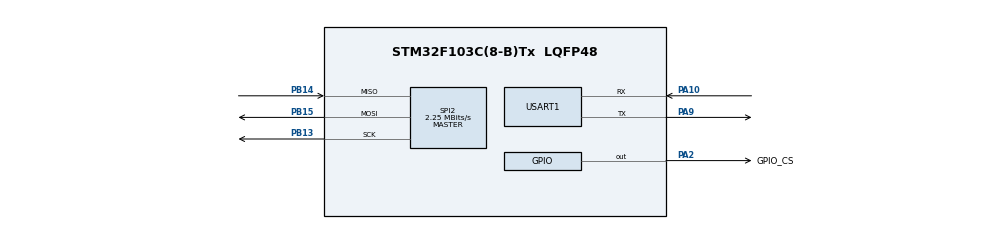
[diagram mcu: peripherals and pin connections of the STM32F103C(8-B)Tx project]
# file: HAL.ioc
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Mcu.Family=STM32F1
Mcu.Name=STM32F103C(8-B)Tx
Mcu.Package=LQFP48
NVIC.PriorityGroup=NVIC_PRIORITYGROUP_4
PA2.GPIO_Label=GPIO_CS
PA2.Signal=GPIO_Output
PA9.Mode=Asynchronous
PA9.Signal=USART1_TX
PA10.Mode=Asynchronous
PA10.Signal=USART1_RX
PA13.Mode=Serial_Wire
PA13.Signal=SYS_JTMS-SWDIO
PA14.Mode=Serial_Wire
PA14.Signal=SYS_JTCK-SWCLK
PB13.Mode=NSS_Signal_Hard_Or_Soft
PB13.Signal=SPI2_SCK
PB14.Mode=NSS_Signal_Hard_Or_Soft
PB14.Signal=SPI2_MISO
PB15.Mode=NSS_Signal_Hard_Or_Soft
PB15.Signal=SPI2_MOSI
ProjectManager.HeapSize=0x200
ProjectManager.StackSize=0x400
ProjectManager.TargetToolchain=MDK-ARM V5.32
RCC.AHBFreq_Value=72000000
RCC.APB1Freq_Value=36000000
RCC.APB1TimFreq_Value=72000000
RCC.APB2Freq_Value=72000000
RCC.APB2TimFreq_Value=72000000
RCC.HCLKFreq_Value=72000000
RCC.HSE_VALUE=8000000
RCC.HSI_VALUE=8000000
RCC.PLLMUL=RCC_PLL_MUL9
RCC.SYSCLKFreq_VALUE=72000000
RCC.SYSCLKSource=RCC_SYSCLKSOURCE_PLLCLK
RCC.USBFreq_Value=36000000
SPI2.CalculateBaudRate=2.25 MBits/s
SPI2.Direction=SPI_DIRECTION_2LINES
SPI2.Mode=SPI_MODE_MASTER
SPI2.BaudRatePrescaler=SPI_BAUDRATEPRESCALER_16
SPI2.VirtualType=VM_MASTER
board=custom

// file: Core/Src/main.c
/* USER CODE BEGIN Header */
/**
  ******************************************************************************
  * @file           : main.c
  * @brief          : Main program body
  ******************************************************************************
  * @attention
  *
  * Copyright (c) 2026 STMicroelectronics.
  * All rights reserved.
  *
  * This software is licensed under terms that can be found in the LICENSE file
  * in the root directory of this software component.
  * If no LICENSE file comes with this software, it is provided AS-IS.
  *
  ******************************************************************************
  */
/* USER CODE END Header */
#include "main.h"
#include "gpio.h"
#include "spi.h"
#include "usart.h"

/* USER CODE BEGIN Includes */
#include "g356_driver.h"
/* USER CODE END Includes */

void SystemClock_Config(void);

/* USER CODE BEGIN 0 */

// ==========================================================================
// G356 SPI Receiver Demo
//
// This file only demonstrates how to call the reusable G356 driver
// (g356_driver.h/.c). If you're integrating G356 into your own product,
// you only need to copy g356_driver.h/.c — the retry loop, success/fail
// statistics, and pretty-printing below are demo-only and can be deleted.
//
// Wiring and protocol details: see g356_driver.h and ../README.md.
// ==========================================================================

// ==========================================
// 调试串口输出辅助函数 (避免依赖大体积的 C 库 printf 及其浮点支持)
// ==========================================
static void G356_UART_PrintString(const char *str)
{
    while (*str) {
        HAL_UART_Transmit(&huart1, (uint8_t *)str, 1, 10);
        str++;
    }
}

static void G356_UART_PrintUint(uint32_t val)
{
    char buf[12];
    int i = 11;
    buf[i] = '\0';
    if (val == 0) {
        G356_UART_PrintString("0");
        return;
    }
    while (val > 0) {
        i--;
        buf[i] = (val % 10) + '0';
        val /= 10;
    }
    G356_UART_PrintString(&buf[i]);
}

static void G356_UART_PrintHex8(uint8_t val)
{
    const char hex_chars[] = "0123456789ABCDEF";
    char buf[3];
    buf[0] = hex_chars[(val >> 4) & 0x0F];
    buf[1] = hex_chars[val & 0x0F];
    buf[2] = '\0';
    G356_UART_PrintString(buf);
}

static void G356_UART_PrintFloat(float val, int decimals)
{
    // 处理负数
    if (val < 0.0f) {
        G356_UART_PrintString("-");
        val = -val;
    }

    // 四舍五入处理
    float rounding = 0.5f;
    for (int d = 0; d < decimals; d++) {
        rounding /= 10.0f;
    }
    val += rounding;

    // 整数部分
    uint32_t int_part = (uint32_t)val;
    G356_UART_PrintUint(int_part);

    // 小数部分
    if (decimals > 0) {
        G356_UART_PrintString(".");
        float frac = val - (float)int_part;
        for (int d = 0; d < decimals; d++) {
            frac *= 10.0f;
            uint32_t digit = (uint32_t)frac;
            G356_UART_PrintUint(digit);
            frac -= (float)digit;
        }
    }
}

/* USER CODE END 0 */

int main(void)
{

  /* MCU Configuration--------------------------------------------------------*/

  /* Reset of all peripherals, Initializes the Flash interface and the Systick. */
  HAL_Init();

  /* Configure the system clock */
  SystemClock_Config();

  /* Initialize all configured peripherals */
  MX_GPIO_Init();
  MX_SPI2_Init();
  MX_USART1_UART_Init();
  /* USER CODE BEGIN 2 */

  HAL_Delay(1000); // 等待 G356 模块内部系统彻底启动并稳定

  G356_UART_PrintString("\r\n");
  G356_UART_PrintString("=========================================\r\n");
  G356_UART_PrintString("   G356 AHRS Module SPI Receiver Demo    \r\n");
  G356_UART_PrintString("   MCU: STM32F103C8T6 | Baudrate: 115200 \r\n");
  G356_UART_PrintString("   Communication: SPI2 (Mode 0, ~2MHz)   \r\n");
  G356_UART_PrintString("=========================================\r\n");
  G356_UART_PrintString("Starting data reading...\r\n");

  uint8_t rx_raw_buf[G356_MAX_FRAME_SIZE]; // 原始接收缓冲区
  uint16_t rx_frame_size = 0;
  G356_Data_t g356_data;               // 解析后的姿态数据结构体
  uint32_t success_count = 0;          // 成功包计数
  uint32_t fail_count = 0;             // 失败包计数

  /* USER CODE END 2 */

  /* Infinite loop */
  while (1)
  {

    /* USER CODE BEGIN 3 */
    HAL_Delay(10); // 实现约 100Hz 的轮询读取速率

    // 根据帧头长度读取当前固件配置的 48/56/72 字节遥测帧。
    bool read_ok = false;
    for (int retry = 0; retry < 3; retry++) {
        if (G356_ReadFrame(rx_raw_buf, &rx_frame_size)) {
            read_ok = true;
            break;
        }
        HAL_Delay(1); // 每次失败后等待从机复位/预装载完毕再试
    }

    if (read_ok) {
        success_count++;

        G356_ParseData(rx_raw_buf, &g356_data);

        // 每成功读取 20 次 (约 200ms) 打印一次数据，防止串口拥堵
        if (success_count % 20 == 0) {
            G356_UART_PrintString("ANG[R:");
            G356_UART_PrintFloat(g356_data.roll, 2);
            G356_UART_PrintString(", P:");
            G356_UART_PrintFloat(g356_data.pitch, 2);
            G356_UART_PrintString(", Y:");
            G356_UART_PrintFloat(g356_data.yaw, 2);

            G356_UART_PrintString("] deg | ACC[");
            G356_UART_PrintFloat(g356_data.accel_x, 3);
            G356_UART_PrintString(", ");
            G356_UART_PrintFloat(g356_data.accel_y, 3);
            G356_UART_PrintString(", ");
            G356_UART_PrintFloat(g356_data.accel_z, 3);

            G356_UART_PrintString("] g | GYR[");
            G356_UART_PrintFloat(g356_data.gyro_x, 1);
            G356_UART_PrintString(", ");
            G356_UART_PrintFloat(g356_data.gyro_y, 1);
            G356_UART_PrintString(", ");
            G356_UART_PrintFloat(g356_data.gyro_z, 1);

            G356_UART_PrintString("] dps | Temp:");
            G356_UART_PrintFloat(g356_data.temp, 1);
            G356_UART_PrintString(" C\r\n");
        }
    } else {
        fail_count++;

        // 每失败 100 次打印一次错误警告和最近一次读取到的前 4 字节数据，方便排查接线或模式问题
        if (fail_count % 100 == 0) {
            G356_UART_PrintString("[Warning] SPI read failed! Success: ");
            G356_UART_PrintUint(success_count);
            G356_UART_PrintString(", Fail: ");
            G356_UART_PrintUint(fail_count);
            G356_UART_PrintString(". Raw: [0x");
            G356_UART_PrintHex8(rx_raw_buf[0]);
            G356_UART_PrintString(", 0x");
            G356_UART_PrintHex8(rx_raw_buf[1]);
            G356_UART_PrintString(", 0x");
            G356_UART_PrintHex8(rx_raw_buf[2]);
            G356_UART_PrintString(", 0x");
            G356_UART_PrintHex8(rx_raw_buf[3]);
            G356_UART_PrintString("]\r\n");
        }
    }
  }
  /* USER CODE END 3 */
}

void SystemClock_Config(void)
{
  RCC_OscInitTypeDef RCC_OscInitStruct = {0};
  RCC_ClkInitTypeDef RCC_ClkInitStruct = {0};

  /** Initializes the RCC Oscillators according to the specified parameters
  * in the RCC_OscInitTypeDef structure.
  */
  RCC_OscInitStruct.OscillatorType = RCC_OSCILLATORTYPE_HSI;
  RCC_OscInitStruct.HSIState = RCC_HSI_ON;
  RCC_OscInitStruct.HSICalibrationValue = RCC_HSICALIBRATION_DEFAULT;
  RCC_OscInitStruct.PLL.PLLState = RCC_PLL_ON;
  RCC_OscInitStruct.PLL.PLLSource = RCC_PLLSOURCE_HSI_DIV2;
  RCC_OscInitStruct.PLL.PLLMUL = RCC_PLL_MUL16;
  if (HAL_RCC_OscConfig(&RCC_OscInitStruct) != HAL_OK)
  {
    Error_Handler();
  }

  /** Initializes the CPU, AHB and APB buses clocks
  */
  RCC_ClkInitStruct.ClockType = RCC_CLOCKTYPE_HCLK|RCC_CLOCKTYPE_SYSCLK
                              |RCC_CLOCKTYPE_PCLK1|RCC_CLOCKTYPE_PCLK2;
  RCC_ClkInitStruct.SYSCLKSource = RCC_SYSCLKSOURCE_PLLCLK;
  RCC_ClkInitStruct.AHBCLKDivider = RCC_SYSCLK_DIV1;
  RCC_ClkInitStruct.APB1CLKDivider = RCC_HCLK_DIV2;
  RCC_ClkInitStruct.APB2CLKDivider = RCC_HCLK_DIV1;

  if (HAL_RCC_ClockConfig(&RCC_ClkInitStruct, FLASH_LATENCY_2) != HAL_OK)
  {
    Error_Handler();
  }
}

void Error_Handler(void)
{
  __disable_irq();
  while (1)
  {
  }
}
